VERSION 5.8 ;
BUSBITCHARS "[]" ;
DIVIDERCHAR "/" ;
UNITS
    DATABASE MICRONS 1000 ;
END UNITS

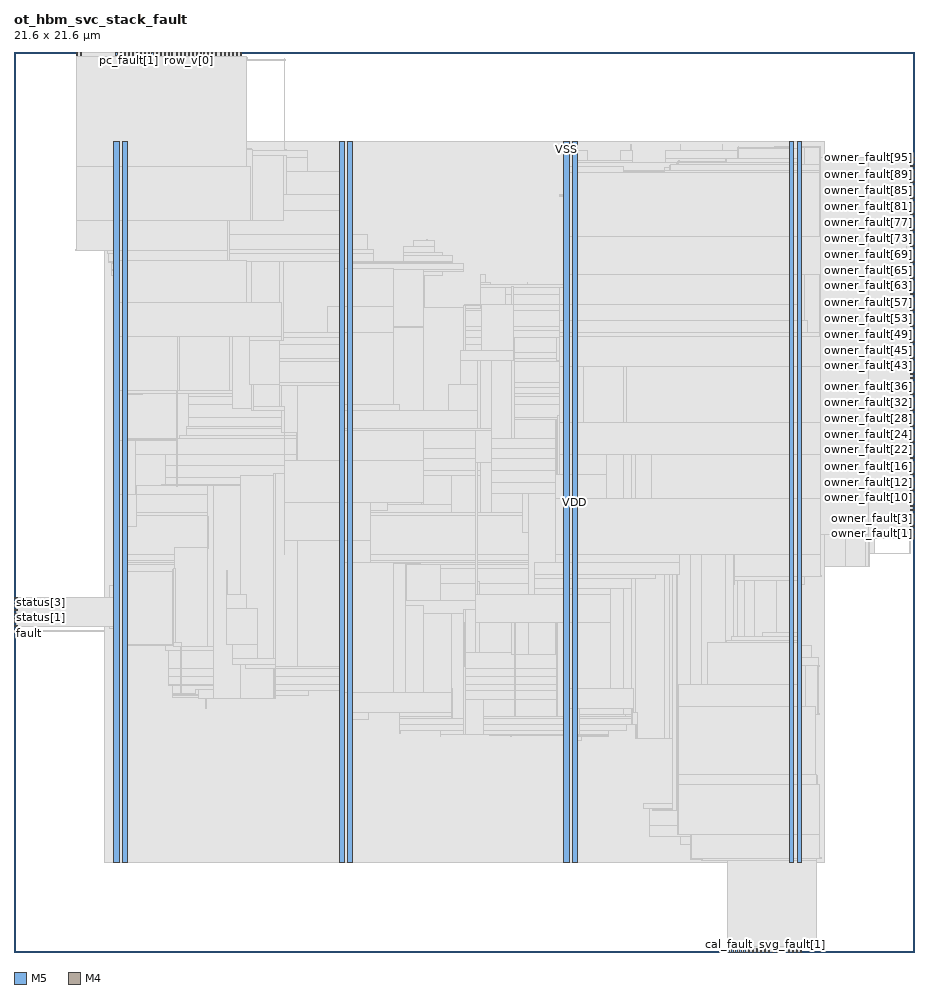
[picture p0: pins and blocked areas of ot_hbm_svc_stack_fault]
MACRO ot_hbm_svc_stack_fault
  FOREIGN ot_hbm_svc_stack_fault 0 0 ;
  CLASS BLOCK ;
  SIZE 21.6 BY 21.6 ;
  PIN cal_fault
    DIRECTION INPUT ;
    USE SIGNAL ;
    PORT
      LAYER M5 ;
        RECT  17.136 0 17.16 0.084 ;
    END
  END cal_fault
  PIN del_fault[0]
    DIRECTION INPUT ;
    USE SIGNAL ;
    PORT
      LAYER M5 ;
        RECT  17.232 0 17.256 0.084 ;
    END
  END del_fault[0]
  PIN del_fault[1]
    DIRECTION INPUT ;
    USE SIGNAL ;
    PORT
      LAYER M5 ;
        RECT  17.328 0 17.352 0.084 ;
    END
  END del_fault[1]
  PIN del_fault[2]
    DIRECTION INPUT ;
    USE SIGNAL ;
    PORT
      LAYER M5 ;
        RECT  17.424 0 17.448 0.084 ;
    END
  END del_fault[2]
  PIN del_fault[3]
    DIRECTION INPUT ;
    USE SIGNAL ;
    PORT
      LAYER M5 ;
        RECT  17.52 0 17.544 0.084 ;
    END
  END del_fault[3]
  PIN del_fault[4]
    DIRECTION INPUT ;
    USE SIGNAL ;
    PORT
      LAYER M5 ;
        RECT  17.616 0 17.64 0.084 ;
    END
  END del_fault[4]
  PIN del_fault[5]
    DIRECTION INPUT ;
    USE SIGNAL ;
    PORT
      LAYER M5 ;
        RECT  17.712 0 17.736 0.084 ;
    END
  END del_fault[5]
  PIN del_fault[6]
    DIRECTION INPUT ;
    USE SIGNAL ;
    PORT
      LAYER M5 ;
        RECT  17.808 0 17.832 0.084 ;
    END
  END del_fault[6]
  PIN del_fault[7]
    DIRECTION INPUT ;
    USE SIGNAL ;
    PORT
      LAYER M5 ;
        RECT  17.904 0 17.928 0.084 ;
    END
  END del_fault[7]
  PIN fault
    DIRECTION OUTPUT ;
    USE SIGNAL ;
    PORT
      LAYER M4 ;
        RECT  0 7.824 0.084 7.848 ;
    END
  END fault
  PIN hbm_clk
    DIRECTION INPUT ;
    USE SIGNAL ;
    PORT
      LAYER M5 ;
        RECT  2.448 21.516 2.472 21.6 ;
    END
  END hbm_clk
  PIN hbm_rst_n
    DIRECTION INPUT ;
    USE SIGNAL ;
    PORT
      LAYER M5 ;
        RECT  2.544 21.516 2.568 21.6 ;
    END
  END hbm_rst_n
  PIN owner_fault[0]
    DIRECTION INPUT ;
    USE SIGNAL ;
    PORT
      LAYER M4 ;
        RECT  21.516 9.936 21.6 9.96 ;
    END
  END owner_fault[0]
  PIN owner_fault[10]
    DIRECTION INPUT ;
    USE SIGNAL ;
    PORT
      LAYER M4 ;
        RECT  21.516 10.896 21.6 10.92 ;
    END
  END owner_fault[10]
  PIN owner_fault[11]
    DIRECTION INPUT ;
    USE SIGNAL ;
    PORT
      LAYER M4 ;
        RECT  21.516 10.992 21.6 11.016 ;
    END
  END owner_fault[11]
  PIN owner_fault[12]
    DIRECTION INPUT ;
    USE SIGNAL ;
    PORT
      LAYER M4 ;
        RECT  21.516 11.088 21.6 11.112 ;
    END
  END owner_fault[12]
  PIN owner_fault[13]
    DIRECTION INPUT ;
    USE SIGNAL ;
    PORT
      LAYER M4 ;
        RECT  21.516 11.184 21.6 11.208 ;
    END
  END owner_fault[13]
  PIN owner_fault[14]
    DIRECTION INPUT ;
    USE SIGNAL ;
    PORT
      LAYER M4 ;
        RECT  21.516 11.28 21.6 11.304 ;
    END
  END owner_fault[14]
  PIN owner_fault[15]
    DIRECTION INPUT ;
    USE SIGNAL ;
    PORT
      LAYER M4 ;
        RECT  21.516 11.376 21.6 11.4 ;
    END
  END owner_fault[15]
  PIN owner_fault[16]
    DIRECTION INPUT ;
    USE SIGNAL ;
    PORT
      LAYER M4 ;
        RECT  21.516 11.472 21.6 11.496 ;
    END
  END owner_fault[16]
  PIN owner_fault[17]
    DIRECTION INPUT ;
    USE SIGNAL ;
    PORT
      LAYER M4 ;
        RECT  21.516 11.568 21.6 11.592 ;
    END
  END owner_fault[17]
  PIN owner_fault[18]
    DIRECTION INPUT ;
    USE SIGNAL ;
    PORT
      LAYER M4 ;
        RECT  21.516 11.664 21.6 11.688 ;
    END
  END owner_fault[18]
  PIN owner_fault[19]
    DIRECTION INPUT ;
    USE SIGNAL ;
    PORT
      LAYER M4 ;
        RECT  21.516 11.76 21.6 11.784 ;
    END
  END owner_fault[19]
  PIN owner_fault[1]
    DIRECTION INPUT ;
    USE SIGNAL ;
    PORT
      LAYER M4 ;
        RECT  21.516 10.032 21.6 10.056 ;
    END
  END owner_fault[1]
  PIN owner_fault[20]
    DIRECTION INPUT ;
    USE SIGNAL ;
    PORT
      LAYER M4 ;
        RECT  21.516 11.856 21.6 11.88 ;
    END
  END owner_fault[20]
  PIN owner_fault[21]
    DIRECTION INPUT ;
    USE SIGNAL ;
    PORT
      LAYER M4 ;
        RECT  21.516 11.952 21.6 11.976 ;
    END
  END owner_fault[21]
  PIN owner_fault[22]
    DIRECTION INPUT ;
    USE SIGNAL ;
    PORT
      LAYER M4 ;
        RECT  21.516 12.048 21.6 12.072 ;
    END
  END owner_fault[22]
  PIN owner_fault[23]
    DIRECTION INPUT ;
    USE SIGNAL ;
    PORT
      LAYER M4 ;
        RECT  21.516 12.144 21.6 12.168 ;
    END
  END owner_fault[23]
  PIN owner_fault[24]
    DIRECTION INPUT ;
    USE SIGNAL ;
    PORT
      LAYER M4 ;
        RECT  21.516 12.24 21.6 12.264 ;
    END
  END owner_fault[24]
  PIN owner_fault[25]
    DIRECTION INPUT ;
    USE SIGNAL ;
    PORT
      LAYER M4 ;
        RECT  21.516 12.336 21.6 12.36 ;
    END
  END owner_fault[25]
  PIN owner_fault[26]
    DIRECTION INPUT ;
    USE SIGNAL ;
    PORT
      LAYER M4 ;
        RECT  21.516 12.432 21.6 12.456 ;
    END
  END owner_fault[26]
  PIN owner_fault[27]
    DIRECTION INPUT ;
    USE SIGNAL ;
    PORT
      LAYER M4 ;
        RECT  21.516 12.528 21.6 12.552 ;
    END
  END owner_fault[27]
  PIN owner_fault[28]
    DIRECTION INPUT ;
    USE SIGNAL ;
    PORT
      LAYER M4 ;
        RECT  21.516 12.624 21.6 12.648 ;
    END
  END owner_fault[28]
  PIN owner_fault[29]
    DIRECTION INPUT ;
    USE SIGNAL ;
    PORT
      LAYER M4 ;
        RECT  21.516 12.72 21.6 12.744 ;
    END
  END owner_fault[29]
  PIN owner_fault[2]
    DIRECTION INPUT ;
    USE SIGNAL ;
    PORT
      LAYER M4 ;
        RECT  21.516 10.128 21.6 10.152 ;
    END
  END owner_fault[2]
  PIN owner_fault[30]
    DIRECTION INPUT ;
    USE SIGNAL ;
    PORT
      LAYER M4 ;
        RECT  21.516 12.816 21.6 12.84 ;
    END
  END owner_fault[30]
  PIN owner_fault[31]
    DIRECTION INPUT ;
    USE SIGNAL ;
    PORT
      LAYER M4 ;
        RECT  21.516 12.912 21.6 12.936 ;
    END
  END owner_fault[31]
  PIN owner_fault[32]
    DIRECTION INPUT ;
    USE SIGNAL ;
    PORT
      LAYER M4 ;
        RECT  21.516 13.008 21.6 13.032 ;
    END
  END owner_fault[32]
  PIN owner_fault[33]
    DIRECTION INPUT ;
    USE SIGNAL ;
    PORT
      LAYER M4 ;
        RECT  21.516 13.104 21.6 13.128 ;
    END
  END owner_fault[33]
  PIN owner_fault[34]
    DIRECTION INPUT ;
    USE SIGNAL ;
    PORT
      LAYER M4 ;
        RECT  21.516 13.2 21.6 13.224 ;
    END
  END owner_fault[34]
  PIN owner_fault[35]
    DIRECTION INPUT ;
    USE SIGNAL ;
    PORT
      LAYER M4 ;
        RECT  21.516 13.296 21.6 13.32 ;
    END
  END owner_fault[35]
  PIN owner_fault[36]
    DIRECTION INPUT ;
    USE SIGNAL ;
    PORT
      LAYER M4 ;
        RECT  21.516 13.392 21.6 13.416 ;
    END
  END owner_fault[36]
  PIN owner_fault[37]
    DIRECTION INPUT ;
    USE SIGNAL ;
    PORT
      LAYER M4 ;
        RECT  21.516 13.488 21.6 13.512 ;
    END
  END owner_fault[37]
  PIN owner_fault[38]
    DIRECTION INPUT ;
    USE SIGNAL ;
    PORT
      LAYER M4 ;
        RECT  21.516 13.584 21.6 13.608 ;
    END
  END owner_fault[38]
  PIN owner_fault[39]
    DIRECTION INPUT ;
    USE SIGNAL ;
    PORT
      LAYER M4 ;
        RECT  21.516 13.68 21.6 13.704 ;
    END
  END owner_fault[39]
  PIN owner_fault[3]
    DIRECTION INPUT ;
    USE SIGNAL ;
    PORT
      LAYER M4 ;
        RECT  21.516 10.224 21.6 10.248 ;
    END
  END owner_fault[3]
  PIN owner_fault[40]
    DIRECTION INPUT ;
    USE SIGNAL ;
    PORT
      LAYER M4 ;
        RECT  21.516 13.776 21.6 13.8 ;
    END
  END owner_fault[40]
  PIN owner_fault[41]
    DIRECTION INPUT ;
    USE SIGNAL ;
    PORT
      LAYER M4 ;
        RECT  21.516 13.872 21.6 13.896 ;
    END
  END owner_fault[41]
  PIN owner_fault[42]
    DIRECTION INPUT ;
    USE SIGNAL ;
    PORT
      LAYER M4 ;
        RECT  21.516 13.968 21.6 13.992 ;
    END
  END owner_fault[42]
  PIN owner_fault[43]
    DIRECTION INPUT ;
    USE SIGNAL ;
    PORT
      LAYER M4 ;
        RECT  21.516 14.064 21.6 14.088 ;
    END
  END owner_fault[43]
  PIN owner_fault[44]
    DIRECTION INPUT ;
    USE SIGNAL ;
    PORT
      LAYER M4 ;
        RECT  21.516 14.16 21.6 14.184 ;
    END
  END owner_fault[44]
  PIN owner_fault[45]
    DIRECTION INPUT ;
    USE SIGNAL ;
    PORT
      LAYER M4 ;
        RECT  21.516 14.256 21.6 14.28 ;
    END
  END owner_fault[45]
  PIN owner_fault[46]
    DIRECTION INPUT ;
    USE SIGNAL ;
    PORT
      LAYER M4 ;
        RECT  21.516 14.352 21.6 14.376 ;
    END
  END owner_fault[46]
  PIN owner_fault[47]
    DIRECTION INPUT ;
    USE SIGNAL ;
    PORT
      LAYER M4 ;
        RECT  21.516 14.448 21.6 14.472 ;
    END
  END owner_fault[47]
  PIN owner_fault[48]
    DIRECTION INPUT ;
    USE SIGNAL ;
    PORT
      LAYER M4 ;
        RECT  21.516 14.544 21.6 14.568 ;
    END
  END owner_fault[48]
  PIN owner_fault[49]
    DIRECTION INPUT ;
    USE SIGNAL ;
    PORT
      LAYER M4 ;
        RECT  21.516 14.64 21.6 14.664 ;
    END
  END owner_fault[49]
  PIN owner_fault[4]
    DIRECTION INPUT ;
    USE SIGNAL ;
    PORT
      LAYER M4 ;
        RECT  21.516 10.32 21.6 10.344 ;
    END
  END owner_fault[4]
  PIN owner_fault[50]
    DIRECTION INPUT ;
    USE SIGNAL ;
    PORT
      LAYER M4 ;
        RECT  21.516 14.736 21.6 14.76 ;
    END
  END owner_fault[50]
  PIN owner_fault[51]
    DIRECTION INPUT ;
    USE SIGNAL ;
    PORT
      LAYER M4 ;
        RECT  21.516 14.832 21.6 14.856 ;
    END
  END owner_fault[51]
  PIN owner_fault[52]
    DIRECTION INPUT ;
    USE SIGNAL ;
    PORT
      LAYER M4 ;
        RECT  21.516 14.928 21.6 14.952 ;
    END
  END owner_fault[52]
  PIN owner_fault[53]
    DIRECTION INPUT ;
    USE SIGNAL ;
    PORT
      LAYER M4 ;
        RECT  21.516 15.024 21.6 15.048 ;
    END
  END owner_fault[53]
  PIN owner_fault[54]
    DIRECTION INPUT ;
    USE SIGNAL ;
    PORT
      LAYER M4 ;
        RECT  21.516 15.12 21.6 15.144 ;
    END
  END owner_fault[54]
  PIN owner_fault[55]
    DIRECTION INPUT ;
    USE SIGNAL ;
    PORT
      LAYER M4 ;
        RECT  21.516 15.216 21.6 15.24 ;
    END
  END owner_fault[55]
  PIN owner_fault[56]
    DIRECTION INPUT ;
    USE SIGNAL ;
    PORT
      LAYER M4 ;
        RECT  21.516 15.312 21.6 15.336 ;
    END
  END owner_fault[56]
  PIN owner_fault[57]
    DIRECTION INPUT ;
    USE SIGNAL ;
    PORT
      LAYER M4 ;
        RECT  21.516 15.408 21.6 15.432 ;
    END
  END owner_fault[57]
  PIN owner_fault[58]
    DIRECTION INPUT ;
    USE SIGNAL ;
    PORT
      LAYER M4 ;
        RECT  21.516 15.504 21.6 15.528 ;
    END
  END owner_fault[58]
  PIN owner_fault[59]
    DIRECTION INPUT ;
    USE SIGNAL ;
    PORT
      LAYER M4 ;
        RECT  21.516 15.6 21.6 15.624 ;
    END
  END owner_fault[59]
  PIN owner_fault[5]
    DIRECTION INPUT ;
    USE SIGNAL ;
    PORT
      LAYER M4 ;
        RECT  21.516 10.416 21.6 10.44 ;
    END
  END owner_fault[5]
  PIN owner_fault[60]
    DIRECTION INPUT ;
    USE SIGNAL ;
    PORT
      LAYER M4 ;
        RECT  21.516 15.696 21.6 15.72 ;
    END
  END owner_fault[60]
  PIN owner_fault[61]
    DIRECTION INPUT ;
    USE SIGNAL ;
    PORT
      LAYER M4 ;
        RECT  21.516 15.792 21.6 15.816 ;
    END
  END owner_fault[61]
  PIN owner_fault[62]
    DIRECTION INPUT ;
    USE SIGNAL ;
    PORT
      LAYER M4 ;
        RECT  21.516 15.888 21.6 15.912 ;
    END
  END owner_fault[62]
  PIN owner_fault[63]
    DIRECTION INPUT ;
    USE SIGNAL ;
    PORT
      LAYER M4 ;
        RECT  21.516 15.984 21.6 16.008 ;
    END
  END owner_fault[63]
  PIN owner_fault[64]
    DIRECTION INPUT ;
    USE SIGNAL ;
    PORT
      LAYER M4 ;
        RECT  21.516 16.08 21.6 16.104 ;
    END
  END owner_fault[64]
  PIN owner_fault[65]
    DIRECTION INPUT ;
    USE SIGNAL ;
    PORT
      LAYER M4 ;
        RECT  21.516 16.176 21.6 16.2 ;
    END
  END owner_fault[65]
  PIN owner_fault[66]
    DIRECTION INPUT ;
    USE SIGNAL ;
    PORT
      LAYER M4 ;
        RECT  21.516 16.272 21.6 16.296 ;
    END
  END owner_fault[66]
  PIN owner_fault[67]
    DIRECTION INPUT ;
    USE SIGNAL ;
    PORT
      LAYER M4 ;
        RECT  21.516 16.368 21.6 16.392 ;
    END
  END owner_fault[67]
  PIN owner_fault[68]
    DIRECTION INPUT ;
    USE SIGNAL ;
    PORT
      LAYER M4 ;
        RECT  21.516 16.464 21.6 16.488 ;
    END
  END owner_fault[68]
  PIN owner_fault[69]
    DIRECTION INPUT ;
    USE SIGNAL ;
    PORT
      LAYER M4 ;
        RECT  21.516 16.56 21.6 16.584 ;
    END
  END owner_fault[69]
  PIN owner_fault[6]
    DIRECTION INPUT ;
    USE SIGNAL ;
    PORT
      LAYER M4 ;
        RECT  21.516 10.512 21.6 10.536 ;
    END
  END owner_fault[6]
  PIN owner_fault[70]
    DIRECTION INPUT ;
    USE SIGNAL ;
    PORT
      LAYER M4 ;
        RECT  21.516 16.656 21.6 16.68 ;
    END
  END owner_fault[70]
  PIN owner_fault[71]
    DIRECTION INPUT ;
    USE SIGNAL ;
    PORT
      LAYER M4 ;
        RECT  21.516 16.752 21.6 16.776 ;
    END
  END owner_fault[71]
  PIN owner_fault[72]
    DIRECTION INPUT ;
    USE SIGNAL ;
    PORT
      LAYER M4 ;
        RECT  21.516 16.848 21.6 16.872 ;
    END
  END owner_fault[72]
  PIN owner_fault[73]
    DIRECTION INPUT ;
    USE SIGNAL ;
    PORT
      LAYER M4 ;
        RECT  21.516 16.944 21.6 16.968 ;
    END
  END owner_fault[73]
  PIN owner_fault[74]
    DIRECTION INPUT ;
    USE SIGNAL ;
    PORT
      LAYER M4 ;
        RECT  21.516 17.04 21.6 17.064 ;
    END
  END owner_fault[74]
  PIN owner_fault[75]
    DIRECTION INPUT ;
    USE SIGNAL ;
    PORT
      LAYER M4 ;
        RECT  21.516 17.136 21.6 17.16 ;
    END
  END owner_fault[75]
  PIN owner_fault[76]
    DIRECTION INPUT ;
    USE SIGNAL ;
    PORT
      LAYER M4 ;
        RECT  21.516 17.232 21.6 17.256 ;
    END
  END owner_fault[76]
  PIN owner_fault[77]
    DIRECTION INPUT ;
    USE SIGNAL ;
    PORT
      LAYER M4 ;
        RECT  21.516 17.328 21.6 17.352 ;
    END
  END owner_fault[77]
  PIN owner_fault[78]
    DIRECTION INPUT ;
    USE SIGNAL ;
    PORT
      LAYER M4 ;
        RECT  21.516 17.424 21.6 17.448 ;
    END
  END owner_fault[78]
  PIN owner_fault[79]
    DIRECTION INPUT ;
    USE SIGNAL ;
    PORT
      LAYER M4 ;
        RECT  21.516 17.52 21.6 17.544 ;
    END
  END owner_fault[79]
  PIN owner_fault[7]
    DIRECTION INPUT ;
    USE SIGNAL ;
    PORT
      LAYER M4 ;
        RECT  21.516 10.608 21.6 10.632 ;
    END
  END owner_fault[7]
  PIN owner_fault[80]
    DIRECTION INPUT ;
    USE SIGNAL ;
    PORT
      LAYER M4 ;
        RECT  21.516 17.616 21.6 17.64 ;
    END
  END owner_fault[80]
  PIN owner_fault[81]
    DIRECTION INPUT ;
    USE SIGNAL ;
    PORT
      LAYER M4 ;
        RECT  21.516 17.712 21.6 17.736 ;
    END
  END owner_fault[81]
  PIN owner_fault[82]
    DIRECTION INPUT ;
    USE SIGNAL ;
    PORT
      LAYER M4 ;
        RECT  21.516 17.808 21.6 17.832 ;
    END
  END owner_fault[82]
  PIN owner_fault[83]
    DIRECTION INPUT ;
    USE SIGNAL ;
    PORT
      LAYER M4 ;
        RECT  21.516 17.904 21.6 17.928 ;
    END
  END owner_fault[83]
  PIN owner_fault[84]
    DIRECTION INPUT ;
    USE SIGNAL ;
    PORT
      LAYER M4 ;
        RECT  21.516 18 21.6 18.024 ;
    END
  END owner_fault[84]
  PIN owner_fault[85]
    DIRECTION INPUT ;
    USE SIGNAL ;
    PORT
      LAYER M4 ;
        RECT  21.516 18.096 21.6 18.12 ;
    END
  END owner_fault[85]
  PIN owner_fault[86]
    DIRECTION INPUT ;
    USE SIGNAL ;
    PORT
      LAYER M4 ;
        RECT  21.516 18.192 21.6 18.216 ;
    END
  END owner_fault[86]
  PIN owner_fault[87]
    DIRECTION INPUT ;
    USE SIGNAL ;
    PORT
      LAYER M4 ;
        RECT  21.516 18.288 21.6 18.312 ;
    END
  END owner_fault[87]
  PIN owner_fault[88]
    DIRECTION INPUT ;
    USE SIGNAL ;
    PORT
      LAYER M4 ;
        RECT  21.516 18.384 21.6 18.408 ;
    END
  END owner_fault[88]
  PIN owner_fault[89]
    DIRECTION INPUT ;
    USE SIGNAL ;
    PORT
      LAYER M4 ;
        RECT  21.516 18.48 21.6 18.504 ;
    END
  END owner_fault[89]
  PIN owner_fault[8]
    DIRECTION INPUT ;
    USE SIGNAL ;
    PORT
      LAYER M4 ;
        RECT  21.516 10.704 21.6 10.728 ;
    END
  END owner_fault[8]
  PIN owner_fault[90]
    DIRECTION INPUT ;
    USE SIGNAL ;
    PORT
      LAYER M4 ;
        RECT  21.516 18.576 21.6 18.6 ;
    END
  END owner_fault[90]
  PIN owner_fault[91]
    DIRECTION INPUT ;
    USE SIGNAL ;
    PORT
      LAYER M4 ;
        RECT  21.516 18.672 21.6 18.696 ;
    END
  END owner_fault[91]
  PIN owner_fault[92]
    DIRECTION INPUT ;
    USE SIGNAL ;
    PORT
      LAYER M4 ;
        RECT  21.516 18.768 21.6 18.792 ;
    END
  END owner_fault[92]
  PIN owner_fault[93]
    DIRECTION INPUT ;
    USE SIGNAL ;
    PORT
      LAYER M4 ;
        RECT  21.516 18.864 21.6 18.888 ;
    END
  END owner_fault[93]
  PIN owner_fault[94]
    DIRECTION INPUT ;
    USE SIGNAL ;
    PORT
      LAYER M4 ;
        RECT  21.516 18.96 21.6 18.984 ;
    END
  END owner_fault[94]
  PIN owner_fault[95]
    DIRECTION INPUT ;
    USE SIGNAL ;
    PORT
      LAYER M4 ;
        RECT  21.516 19.056 21.6 19.08 ;
    END
  END owner_fault[95]
  PIN owner_fault[9]
    DIRECTION INPUT ;
    USE SIGNAL ;
    PORT
      LAYER M4 ;
        RECT  21.516 10.8 21.6 10.824 ;
    END
  END owner_fault[9]
  PIN pc_fault[0]
    DIRECTION INPUT ;
    USE SIGNAL ;
    PORT
      LAYER M5 ;
        RECT  2.64 21.516 2.664 21.6 ;
    END
  END pc_fault[0]
  PIN pc_fault[10]
    DIRECTION INPUT ;
    USE SIGNAL ;
    PORT
      LAYER M5 ;
        RECT  3.6 21.516 3.624 21.6 ;
    END
  END pc_fault[10]
  PIN pc_fault[11]
    DIRECTION INPUT ;
    USE SIGNAL ;
    PORT
      LAYER M5 ;
        RECT  3.696 21.516 3.72 21.6 ;
    END
  END pc_fault[11]
  PIN pc_fault[12]
    DIRECTION INPUT ;
    USE SIGNAL ;
    PORT
      LAYER M5 ;
        RECT  3.792 21.516 3.816 21.6 ;
    END
  END pc_fault[12]
  PIN pc_fault[13]
    DIRECTION INPUT ;
    USE SIGNAL ;
    PORT
      LAYER M5 ;
        RECT  3.888 21.516 3.912 21.6 ;
    END
  END pc_fault[13]
  PIN pc_fault[14]
    DIRECTION INPUT ;
    USE SIGNAL ;
    PORT
      LAYER M5 ;
        RECT  3.984 21.516 4.008 21.6 ;
    END
  END pc_fault[14]
  PIN pc_fault[15]
    DIRECTION INPUT ;
    USE SIGNAL ;
    PORT
      LAYER M5 ;
        RECT  4.08 21.516 4.104 21.6 ;
    END
  END pc_fault[15]
  PIN pc_fault[1]
    DIRECTION INPUT ;
    USE SIGNAL ;
    PORT
      LAYER M5 ;
        RECT  2.736 21.516 2.76 21.6 ;
    END
  END pc_fault[1]
  PIN pc_fault[2]
    DIRECTION INPUT ;
    USE SIGNAL ;
    PORT
      LAYER M5 ;
        RECT  2.832 21.516 2.856 21.6 ;
    END
  END pc_fault[2]
  PIN pc_fault[3]
    DIRECTION INPUT ;
    USE SIGNAL ;
    PORT
      LAYER M5 ;
        RECT  2.928 21.516 2.952 21.6 ;
    END
  END pc_fault[3]
  PIN pc_fault[4]
    DIRECTION INPUT ;
    USE SIGNAL ;
    PORT
      LAYER M5 ;
        RECT  3.024 21.516 3.048 21.6 ;
    END
  END pc_fault[4]
  PIN pc_fault[5]
    DIRECTION INPUT ;
    USE SIGNAL ;
    PORT
      LAYER M5 ;
        RECT  3.12 21.516 3.144 21.6 ;
    END
  END pc_fault[5]
  PIN pc_fault[6]
    DIRECTION INPUT ;
    USE SIGNAL ;
    PORT
      LAYER M5 ;
        RECT  3.216 21.516 3.24 21.6 ;
    END
  END pc_fault[6]
  PIN pc_fault[7]
    DIRECTION INPUT ;
    USE SIGNAL ;
    PORT
      LAYER M5 ;
        RECT  3.312 21.516 3.336 21.6 ;
    END
  END pc_fault[7]
  PIN pc_fault[8]
    DIRECTION INPUT ;
    USE SIGNAL ;
    PORT
      LAYER M5 ;
        RECT  3.408 21.516 3.432 21.6 ;
    END
  END pc_fault[8]
  PIN pc_fault[9]
    DIRECTION INPUT ;
    USE SIGNAL ;
    PORT
      LAYER M5 ;
        RECT  3.504 21.516 3.528 21.6 ;
    END
  END pc_fault[9]
  PIN row_v[0]
    DIRECTION INPUT ;
    USE SIGNAL ;
    PORT
      LAYER M5 ;
        RECT  4.176 21.516 4.2 21.6 ;
    END
  END row_v[0]
  PIN row_v[10]
    DIRECTION INPUT ;
    USE SIGNAL ;
    PORT
      LAYER M5 ;
        RECT  5.136 21.516 5.16 21.6 ;
    END
  END row_v[10]
  PIN row_v[11]
    DIRECTION INPUT ;
    USE SIGNAL ;
    PORT
      LAYER M5 ;
        RECT  5.232 21.516 5.256 21.6 ;
    END
  END row_v[11]
  PIN row_v[12]
    DIRECTION INPUT ;
    USE SIGNAL ;
    PORT
      LAYER M5 ;
        RECT  5.328 21.516 5.352 21.6 ;
    END
  END row_v[12]
  PIN row_v[13]
    DIRECTION INPUT ;
    USE SIGNAL ;
    PORT
      LAYER M5 ;
        RECT  5.424 21.516 5.448 21.6 ;
    END
  END row_v[13]
  PIN row_v[14]
    DIRECTION INPUT ;
    USE SIGNAL ;
    PORT
      LAYER M5 ;
        RECT  1.488 21.516 1.512 21.6 ;
    END
  END row_v[14]
  PIN row_v[15]
    DIRECTION INPUT ;
    USE SIGNAL ;
    PORT
      LAYER M5 ;
        RECT  1.584 21.516 1.608 21.6 ;
    END
  END row_v[15]
  PIN row_v[1]
    DIRECTION INPUT ;
    USE SIGNAL ;
    PORT
      LAYER M5 ;
        RECT  4.272 21.516 4.296 21.6 ;
    END
  END row_v[1]
  PIN row_v[2]
    DIRECTION INPUT ;
    USE SIGNAL ;
    PORT
      LAYER M5 ;
        RECT  4.368 21.516 4.392 21.6 ;
    END
  END row_v[2]
  PIN row_v[3]
    DIRECTION INPUT ;
    USE SIGNAL ;
    PORT
      LAYER M5 ;
        RECT  4.464 21.516 4.488 21.6 ;
    END
  END row_v[3]
  PIN row_v[4]
    DIRECTION INPUT ;
    USE SIGNAL ;
    PORT
      LAYER M5 ;
        RECT  4.56 21.516 4.584 21.6 ;
    END
  END row_v[4]
  PIN row_v[5]
    DIRECTION INPUT ;
    USE SIGNAL ;
    PORT
      LAYER M5 ;
        RECT  4.656 21.516 4.68 21.6 ;
    END
  END row_v[5]
  PIN row_v[6]
    DIRECTION INPUT ;
    USE SIGNAL ;
    PORT
      LAYER M5 ;
        RECT  4.752 21.516 4.776 21.6 ;
    END
  END row_v[6]
  PIN row_v[7]
    DIRECTION INPUT ;
    USE SIGNAL ;
    PORT
      LAYER M5 ;
        RECT  4.848 21.516 4.872 21.6 ;
    END
  END row_v[7]
  PIN row_v[8]
    DIRECTION INPUT ;
    USE SIGNAL ;
    PORT
      LAYER M5 ;
        RECT  4.944 21.516 4.968 21.6 ;
    END
  END row_v[8]
  PIN row_v[9]
    DIRECTION INPUT ;
    USE SIGNAL ;
    PORT
      LAYER M5 ;
        RECT  5.04 21.516 5.064 21.6 ;
    END
  END row_v[9]
  PIN share_fault[0]
    DIRECTION INPUT ;
    USE SIGNAL ;
    PORT
      LAYER M5 ;
        RECT  18 0 18.024 0.084 ;
    END
  END share_fault[0]
  PIN share_fault[1]
    DIRECTION INPUT ;
    USE SIGNAL ;
    PORT
      LAYER M5 ;
        RECT  18.096 0 18.12 0.084 ;
    END
  END share_fault[1]
  PIN share_fault[2]
    DIRECTION INPUT ;
    USE SIGNAL ;
    PORT
      LAYER M5 ;
        RECT  18.192 0 18.216 0.084 ;
    END
  END share_fault[2]
  PIN share_fault[3]
    DIRECTION INPUT ;
    USE SIGNAL ;
    PORT
      LAYER M5 ;
        RECT  18.288 0 18.312 0.084 ;
    END
  END share_fault[3]
  PIN status[0]
    DIRECTION OUTPUT ;
    USE SIGNAL ;
    PORT
      LAYER M4 ;
        RECT  0 7.92 0.084 7.944 ;
    END
  END status[0]
  PIN status[1]
    DIRECTION OUTPUT ;
    USE SIGNAL ;
    PORT
      LAYER M4 ;
        RECT  0 8.016 0.084 8.04 ;
    END
  END status[1]
  PIN status[2]
    DIRECTION OUTPUT ;
    USE SIGNAL ;
    PORT
      LAYER M4 ;
        RECT  0 8.112 0.084 8.136 ;
    END
  END status[2]
  PIN status[3]
    DIRECTION OUTPUT ;
    USE SIGNAL ;
    PORT
      LAYER M4 ;
        RECT  0 8.208 0.084 8.232 ;
    END
  END status[3]
  PIN status[4]
    DIRECTION OUTPUT ;
    USE SIGNAL ;
    PORT
      LAYER M4 ;
        RECT  0 8.304 0.084 8.328 ;
    END
  END status[4]
  PIN status[5]
    DIRECTION OUTPUT ;
    USE SIGNAL ;
    PORT
      LAYER M4 ;
        RECT  0 8.4 0.084 8.424 ;
    END
  END status[5]
  PIN status[6]
    DIRECTION OUTPUT ;
    USE SIGNAL ;
    PORT
      LAYER M4 ;
        RECT  0 8.496 0.084 8.52 ;
    END
  END status[6]
  PIN stream_clk
    DIRECTION INPUT ;
    USE SIGNAL ;
    PORT
      LAYER M5 ;
        RECT  18.384 0 18.408 0.084 ;
    END
  END stream_clk
  PIN stream_rst_n
    DIRECTION INPUT ;
    USE SIGNAL ;
    PORT
      LAYER M5 ;
        RECT  18.48 0 18.504 0.084 ;
    END
  END stream_rst_n
  PIN svg_fault[0]
    DIRECTION INPUT ;
    USE SIGNAL ;
    PORT
      LAYER M5 ;
        RECT  18.576 0 18.6 0.084 ;
    END
  END svg_fault[0]
  PIN svg_fault[1]
    DIRECTION INPUT ;
    USE SIGNAL ;
    PORT
      LAYER M5 ;
        RECT  18.672 0 18.696 0.084 ;
    END
  END svg_fault[1]
  PIN svg_fault[2]
    DIRECTION INPUT ;
    USE SIGNAL ;
    PORT
      LAYER M5 ;
        RECT  18.768 0 18.792 0.084 ;
    END
  END svg_fault[2]
  PIN svg_fault[3]
    DIRECTION INPUT ;
    USE SIGNAL ;
    PORT
      LAYER M5 ;
        RECT  18.864 0 18.888 0.084 ;
    END
  END svg_fault[3]
  PIN VDD
    DIRECTION INOUT ;
    USE POWER ;
    PORT
      LAYER M5 ;
        RECT  18.792 2.151 18.912 19.449 ;
        RECT  13.392 2.151 13.512 19.449 ;
        RECT  7.992 2.151 8.112 19.449 ;
        RECT  2.592 2.151 2.712 19.449 ;
    END
  END VDD
  PIN VSS
    DIRECTION INOUT ;
    USE GROUND ;
    PORT
      LAYER M5 ;
        RECT  18.6 2.137 18.72 19.463 ;
        RECT  13.2 2.137 13.32 19.463 ;
        RECT  7.8 2.137 7.92 19.463 ;
        RECT  2.4 2.137 2.52 19.463 ;
    END
  END VSS
  OBS
    LAYER RVTN ;
     RECT  2.16 2.16 19.44 2.295 ;
     RECT  2.16 2.565 19.44 2.835 ;
     RECT  2.16 3.105 19.44 3.375 ;
     RECT  2.16 3.645 19.44 3.915 ;
     RECT  2.16 4.185 19.44 4.455 ;
     RECT  2.16 4.725 19.44 4.995 ;
     RECT  2.16 5.265 19.44 5.535 ;
     RECT  2.16 5.805 19.44 6.075 ;
     RECT  2.16 6.345 19.44 6.615 ;
     RECT  2.16 6.885 19.44 7.155 ;
     RECT  2.16 7.425 19.44 7.695 ;
     RECT  2.16 7.965 19.44 8.235 ;
     RECT  2.16 8.505 19.44 8.775 ;
     RECT  2.16 9.045 19.44 9.315 ;
     RECT  2.16 9.585 19.44 9.855 ;
     RECT  2.16 10.125 19.44 10.395 ;
     RECT  2.16 10.665 19.44 10.935 ;
     RECT  2.16 11.205 19.44 11.475 ;
     RECT  2.16 11.745 19.44 12.015 ;
     RECT  2.16 12.285 19.44 12.555 ;
     RECT  2.16 12.825 19.44 13.095 ;
     RECT  2.16 13.365 19.44 13.635 ;
     RECT  2.16 13.905 19.44 14.175 ;
     RECT  2.16 14.445 19.44 14.715 ;
     RECT  2.16 14.985 19.44 15.255 ;
     RECT  2.16 15.525 19.44 15.795 ;
     RECT  2.16 16.065 19.44 16.335 ;
     RECT  2.16 16.605 19.44 16.875 ;
     RECT  2.16 17.145 19.44 17.415 ;
     RECT  2.16 17.685 19.44 17.955 ;
     RECT  2.16 18.225 19.44 18.495 ;
     RECT  2.16 18.765 19.44 19.035 ;
     RECT  2.16 19.305 19.44 19.44 ;
    LAYER RVTP ;
     RECT  2.16 2.295 19.44 2.565 ;
     RECT  2.16 2.835 19.44 3.105 ;
     RECT  2.16 3.375 19.44 3.645 ;
     RECT  2.16 3.915 19.44 4.185 ;
     RECT  2.16 4.455 19.44 4.725 ;
     RECT  2.16 4.995 19.44 5.265 ;
     RECT  2.16 5.535 19.44 5.805 ;
     RECT  2.16 6.075 19.44 6.345 ;
     RECT  2.16 6.615 19.44 6.885 ;
     RECT  2.16 7.155 19.44 7.425 ;
     RECT  2.16 7.695 19.44 7.965 ;
     RECT  2.16 8.235 19.44 8.505 ;
     RECT  2.16 8.775 19.44 9.045 ;
     RECT  2.16 9.315 19.44 9.585 ;
     RECT  2.16 9.855 19.44 10.125 ;
     RECT  2.16 10.395 19.44 10.665 ;
     RECT  2.16 10.935 19.44 11.205 ;
     RECT  2.16 11.475 19.44 11.745 ;
     RECT  2.16 12.015 19.44 12.285 ;
     RECT  2.16 12.555 19.44 12.825 ;
     RECT  2.16 13.095 19.44 13.365 ;
     RECT  2.16 13.635 19.44 13.905 ;
     RECT  2.16 14.175 19.44 14.445 ;
     RECT  2.16 14.715 19.44 14.985 ;
     RECT  2.16 15.255 19.44 15.525 ;
     RECT  2.16 15.795 19.44 16.065 ;
     RECT  2.16 16.335 19.44 16.605 ;
     RECT  2.16 16.875 19.44 17.145 ;
     RECT  2.16 17.415 19.44 17.685 ;
     RECT  2.16 17.955 19.44 18.225 ;
     RECT  2.16 18.495 19.44 18.765 ;
     RECT  2.16 19.035 19.44 19.305 ;
    LAYER M1 ;
     RECT  2.16 2.151 19.44 19.449 ;
    LAYER M2 ;
     RECT  0.535 7.704 2.16 7.722 ;
     RECT  2.16 2.151 19.44 19.449 ;
     RECT  19.44 9.252 19.967 13.392 ;
     RECT  19.44 14.346 19.967 18.99 ;
     RECT  19.967 14.346 20.219 16.398 ;
     RECT  20.219 16.38 20.327 16.398 ;
     RECT  19.967 9.252 20.435 13.32 ;
     RECT  19.967 17.352 20.435 18.99 ;
     RECT  20.219 14.346 20.471 15.318 ;
     RECT  20.435 9.252 20.507 12.474 ;
     RECT  20.435 13.302 20.507 13.32 ;
     RECT  20.471 14.652 20.507 15.318 ;
     RECT  20.435 17.352 20.507 17.37 ;
     RECT  20.435 18.198 20.507 18.99 ;
     RECT  20.507 9.252 20.543 10.764 ;
     RECT  20.507 12.456 20.543 12.474 ;
     RECT  20.543 9.558 20.651 10.188 ;
     RECT  20.507 18.27 21.443 18.45 ;
     RECT  20.651 9.558 21.515 9.576 ;
     RECT  21.415 11.556 21.515 11.574 ;
     RECT  20.507 15.3 21.515 15.318 ;
     RECT  21.443 18.432 21.515 18.45 ;
    LAYER M3 ;
     RECT  17.784 1.723 18.09 1.771 ;
     RECT  17.532 1.771 18.09 2.011 ;
     RECT  18.828 1.723 18.846 2.011 ;
     RECT  17.532 2.011 18.846 2.191 ;
     RECT  16.812 2.191 18.846 2.227 ;
     RECT  16.236 2.227 18.846 2.251 ;
     RECT  16.236 2.251 19.314 2.291 ;
     RECT  2.415 2.143 2.505 2.413 ;
     RECT  7.815 2.143 7.905 2.413 ;
     RECT  13.215 2.143 13.305 2.413 ;
     RECT  16.236 2.291 19.242 2.569 ;
     RECT  15.984 2.569 19.242 2.767 ;
     RECT  15.264 2.767 19.242 3.029 ;
     RECT  15.264 3.029 19.17 3.451 ;
     RECT  15.12 3.451 19.17 3.569 ;
     RECT  15.948 3.569 19.17 3.877 ;
     RECT  15.948 3.877 19.206 4.081 ;
     RECT  15.948 4.081 19.242 4.363 ;
     RECT  15.804 4.363 19.242 4.415 ;
     RECT  16.344 4.415 19.242 4.649 ;
     RECT  13.215 2.413 13.497 5.071 ;
     RECT  13.215 5.071 13.626 5.161 ;
     RECT  11.916 5.161 11.934 5.197 ;
     RECT  13.215 5.161 14.274 5.197 ;
     RECT  10.224 5.161 10.242 5.227 ;
     RECT  11.412 5.197 14.274 5.227 ;
     RECT  9.252 5.233 9.27 5.305 ;
     RECT  10.224 5.227 14.274 5.305 ;
     RECT  9.252 5.305 14.706 5.461 ;
     RECT  7.815 2.413 8.097 5.575 ;
     RECT  9.252 5.461 14.85 5.605 ;
     RECT  9.252 5.605 15.138 5.645 ;
     RECT  16.344 4.649 19.134 5.707 ;
     RECT  7.815 5.575 8.514 5.737 ;
     RECT  9.252 5.645 14.67 5.737 ;
     RECT  4.608 5.845 4.626 6.079 ;
     RECT  4.428 6.079 4.626 6.091 ;
     RECT  4.428 6.091 5.274 6.115 ;
     RECT  6.156 6.079 6.174 6.115 ;
     RECT  3.816 6.115 5.274 6.151 ;
     RECT  6.084 6.115 6.174 6.151 ;
     RECT  6.084 6.151 7.074 6.277 ;
     RECT  7.815 5.737 14.67 6.277 ;
     RECT  15.912 5.707 19.314 6.379 ;
     RECT  3.816 6.151 5.31 6.385 ;
     RECT  3.708 6.385 5.31 6.421 ;
     RECT  6.084 6.277 14.67 6.421 ;
     RECT  3.708 6.421 14.67 6.619 ;
     RECT  3.708 6.619 14.85 6.808 ;
     RECT  15.84 6.379 19.314 7.079 ;
     RECT  3.708 6.808 14.994 7.231 ;
     RECT  15.84 7.079 19.134 7.349 ;
     RECT  2.415 2.413 2.697 7.357 ;
     RECT  3.636 7.231 14.994 7.357 ;
     RECT  2.415 7.357 14.994 7.393 ;
     RECT  15.84 7.349 18.897 7.619 ;
     RECT  16.884 7.619 18.897 7.709 ;
     RECT  2.415 7.393 15.066 7.771 ;
     RECT  15.84 7.619 16.002 7.771 ;
     RECT  2.304 7.771 16.002 7.889 ;
     RECT  16.884 7.709 17.046 7.889 ;
     RECT  17.82 7.709 18.897 7.889 ;
     RECT  16.884 7.889 16.902 7.925 ;
     RECT  17.856 7.889 18.897 8.069 ;
     RECT  0.54 7.699 0.558 8.141 ;
     RECT  2.304 7.889 15.57 8.429 ;
     RECT  2.304 8.429 9.414 8.501 ;
     RECT  2.304 8.501 8.097 8.807 ;
     RECT  18.615 8.069 18.897 8.827 ;
     RECT  10.224 8.429 15.57 8.851 ;
     RECT  18.615 8.827 18.954 8.941 ;
     RECT  17.316 8.941 17.334 8.977 ;
     RECT  18.468 8.941 18.954 9.019 ;
     RECT  18.396 9.019 18.954 9.067 ;
     RECT  17.208 8.977 17.334 9.085 ;
     RECT  18.396 9.067 19.314 9.085 ;
     RECT  17.208 9.085 19.314 9.113 ;
     RECT  10.224 8.851 15.786 9.211 ;
     RECT  2.415 8.807 8.097 9.307 ;
     RECT  8.82 8.501 9.414 9.307 ;
     RECT  10.224 9.211 15.966 9.307 ;
     RECT  2.415 9.307 15.966 9.355 ;
     RECT  2.415 9.355 16.254 9.403 ;
     RECT  17.208 9.113 19.17 9.403 ;
     RECT  2.415 9.403 19.17 9.545 ;
     RECT  17.244 9.545 19.17 9.931 ;
     RECT  20.52 9.247 20.538 10.093 ;
     RECT  20.52 10.093 20.574 10.165 ;
     RECT  21.492 9.553 21.51 10.253 ;
     RECT  20.52 10.165 20.646 10.363 ;
     RECT  20.484 10.363 20.646 10.411 ;
     RECT  2.415 9.545 16.29 10.471 ;
     RECT  17.244 9.931 19.242 10.471 ;
     RECT  2.415 10.471 19.242 10.541 ;
     RECT  16.884 10.541 19.242 10.597 ;
     RECT  20.376 10.411 20.646 10.597 ;
     RECT  16.884 10.597 20.646 10.697 ;
     RECT  21.42 10.363 21.438 10.733 ;
     RECT  19.944 10.697 20.646 10.829 ;
     RECT  2.415 10.541 16.146 11.003 ;
     RECT  2.415 11.003 6.93 11.129 ;
     RECT  3.528 11.129 6.93 11.213 ;
     RECT  7.668 11.003 16.146 11.275 ;
     RECT  16.884 10.697 19.134 11.275 ;
     RECT  3.636 11.213 6.93 11.399 ;
     RECT  7.668 11.275 19.134 11.551 ;
     RECT  21.42 11.515 21.438 11.551 ;
     RECT  21.42 11.551 21.51 11.579 ;
     RECT  21.492 11.579 21.51 11.597 ;
     RECT  3.636 11.399 6.858 11.669 ;
     RECT  20.484 10.829 20.646 11.755 ;
     RECT  7.668 11.551 19.242 11.849 ;
     RECT  2.415 11.129 2.697 11.947 ;
     RECT  3.636 11.669 6.786 11.947 ;
     RECT  20.448 11.755 20.646 11.981 ;
     RECT  20.448 11.981 20.538 12.043 ;
     RECT  7.74 11.849 19.242 12.091 ;
     RECT  2.415 11.947 6.786 12.317 ;
     RECT  3.96 12.317 6.786 12.389 ;
     RECT  4.14 12.389 6.786 12.559 ;
     RECT  4.14 12.559 6.822 12.571 ;
     RECT  7.74 12.091 19.422 12.571 ;
     RECT  4.14 12.571 19.422 12.623 ;
     RECT  4.176 12.623 19.422 12.829 ;
     RECT  20.412 12.043 20.538 12.829 ;
     RECT  4.176 12.829 20.538 13.133 ;
     RECT  4.176 13.133 20.502 13.325 ;
     RECT  2.415 12.317 2.697 13.369 ;
     RECT  2.415 13.369 3.078 13.405 ;
     RECT  4.176 13.325 19.962 13.405 ;
     RECT  2.415 13.405 19.962 13.559 ;
     RECT  3.636 13.559 19.962 13.667 ;
     RECT  3.636 13.667 3.654 13.703 ;
     RECT  2.415 13.559 2.898 13.709 ;
     RECT  21.384 13.723 21.402 13.771 ;
     RECT  21.276 13.771 21.402 13.901 ;
     RECT  4.5 13.667 19.962 14.171 ;
     RECT  4.752 14.171 19.962 14.251 ;
     RECT  4.752 14.251 20.502 14.573 ;
     RECT  2.415 13.709 2.697 14.731 ;
     RECT  4.752 14.573 19.314 14.747 ;
     RECT  2.415 14.731 3.222 14.755 ;
     RECT  2.415 14.755 4.014 14.917 ;
     RECT  4.752 14.747 19.242 14.917 ;
     RECT  20.412 14.573 20.502 14.981 ;
     RECT  2.415 14.917 19.242 15.005 ;
     RECT  9 15.005 9.018 15.215 ;
     RECT  20.412 14.981 20.43 15.251 ;
     RECT  9.828 15.005 19.242 15.389 ;
     RECT  21.492 15.295 21.51 15.403 ;
     RECT  10.8 15.389 19.242 15.533 ;
     RECT  21.42 15.403 21.51 15.629 ;
     RECT  21.42 15.629 21.438 15.691 ;
     RECT  21.276 15.691 21.438 15.821 ;
     RECT  11.196 15.533 19.242 15.835 ;
     RECT  20.196 15.499 20.214 15.835 ;
     RECT  21.42 15.821 21.438 15.965 ;
     RECT  11.196 15.835 20.214 16.025 ;
     RECT  11.196 16.025 11.43 16.061 ;
     RECT  12.312 16.025 12.33 16.061 ;
     RECT  13.215 16.025 20.214 16.075 ;
     RECT  2.415 15.005 8.097 16.231 ;
     RECT  9.828 15.389 9.846 16.231 ;
     RECT  11.196 16.061 11.322 16.259 ;
     RECT  9.828 16.231 10.278 16.339 ;
     RECT  2.34 16.231 8.097 16.363 ;
     RECT  2.34 16.363 8.694 16.375 ;
     RECT  9.828 16.339 10.782 16.375 ;
     RECT  13.215 16.075 20.322 16.403 ;
     RECT  2.34 16.375 10.782 16.529 ;
     RECT  2.34 16.529 10.53 16.537 ;
     RECT  2.268 16.537 10.53 16.565 ;
     RECT  21.348 16.603 21.366 16.651 ;
     RECT  9.36 16.565 10.53 16.709 ;
     RECT  2.268 16.565 8.622 16.771 ;
     RECT  21.276 16.651 21.366 16.781 ;
     RECT  9.36 16.709 10.278 16.799 ;
     RECT  2.232 16.771 8.622 16.871 ;
     RECT  9.36 16.799 10.098 16.943 ;
     RECT  13.215 16.403 19.962 16.979 ;
     RECT  9.576 16.943 10.098 17.069 ;
     RECT  21.348 16.781 21.366 17.069 ;
     RECT  9.9 17.069 9.918 17.105 ;
     RECT  2.232 16.871 8.478 17.213 ;
     RECT  13.215 16.979 19.422 17.213 ;
     RECT  20.412 17.227 20.502 17.375 ;
     RECT  20.412 17.375 20.43 17.707 ;
     RECT  13.215 17.213 19.206 17.753 ;
     RECT  2.232 17.213 8.097 17.789 ;
     RECT  13.215 17.753 19.17 17.879 ;
     RECT  21.42 17.131 21.438 17.899 ;
     RECT  20.376 17.707 20.43 17.951 ;
     RECT  21.276 17.899 21.438 18.029 ;
     RECT  21.384 18.029 21.438 18.091 ;
     RECT  13.215 17.879 19.062 18.139 ;
     RECT  21.384 18.091 21.51 18.173 ;
     RECT  13.104 18.139 19.062 18.185 ;
     RECT  21.42 18.173 21.51 18.317 ;
     RECT  21.492 18.317 21.51 18.455 ;
     RECT  2.268 17.789 8.097 18.689 ;
     RECT  13.215 18.185 19.062 18.763 ;
     RECT  20.448 18.184 20.502 18.869 ;
     RECT  13.215 18.763 19.314 18.959 ;
     RECT  13.215 18.959 14.85 18.995 ;
     RECT  20.484 18.869 20.502 18.995 ;
     RECT  15.624 18.959 19.314 19.051 ;
     RECT  2.268 18.689 7.038 19.067 ;
     RECT  7.815 18.689 8.097 19.187 ;
     RECT  2.304 19.067 7.038 19.229 ;
     RECT  13.215 18.995 13.77 19.229 ;
     RECT  14.544 18.995 14.85 19.229 ;
     RECT  15.624 19.051 19.35 19.229 ;
     RECT  6.48 19.229 6.534 19.265 ;
     RECT  18.18 19.229 19.35 19.265 ;
     RECT  2.304 19.229 5.706 19.277 ;
     RECT  18.252 19.265 19.35 19.325 ;
     RECT  2.304 19.277 5.526 19.337 ;
     RECT  18.252 19.325 18.705 19.337 ;
     RECT  2.304 19.337 4.194 19.373 ;
     RECT  4.968 19.337 5.526 19.373 ;
     RECT  14.796 19.229 14.814 19.373 ;
     RECT  15.984 19.229 16.002 19.373 ;
     RECT  16.992 19.229 17.01 19.373 ;
     RECT  2.415 19.373 2.862 19.379 ;
     RECT  2.415 19.379 2.646 19.457 ;
     RECT  7.815 19.187 7.905 19.457 ;
     RECT  13.215 19.229 13.305 19.457 ;
     RECT  18.615 19.337 18.705 19.457 ;
     RECT  2.628 19.457 2.646 19.565 ;
     RECT  3.888 19.373 3.906 19.613 ;
     RECT  3.06 21.115 3.078 21.163 ;
     RECT  4.824 21.259 4.842 21.307 ;
     RECT  2.952 21.163 3.258 21.437 ;
     RECT  6.48 19.265 6.498 21.437 ;
     RECT  3.096 21.437 3.114 21.485 ;
     RECT  4.644 21.307 4.842 21.485 ;
    LAYER M4 ;
     RECT  1.477 16.848 2.293 16.872 ;
     RECT  1.573 19.344 2.293 19.368 ;
     RECT  0.06 7.824 2.408 8.52 ;
     RECT  2.293 16.848 2.408 17.496 ;
     RECT  2.293 18.816 2.408 19.368 ;
     RECT  2.293 21.264 2.437 21.288 ;
     RECT  2.408 2.148 2.512 19.452 ;
     RECT  2.437 21.12 2.533 21.288 ;
     RECT  2.512 2.418 2.588 19.452 ;
     RECT  2.588 2.418 2.675 19.56 ;
     RECT  2.675 2.418 2.704 19.368 ;
     RECT  2.533 21.12 2.897 21.336 ;
     RECT  2.704 12.24 2.915 12.312 ;
     RECT  2.704 10.224 2.945 11.208 ;
     RECT  2.897 21.12 3.058 21.432 ;
     RECT  3.058 21.12 3.157 21.48 ;
     RECT  3.157 21.024 3.169 21.48 ;
     RECT  3.169 21.024 3.299 21.432 ;
     RECT  3.299 21.168 3.347 21.432 ;
     RECT  2.704 13.488 3.685 19.368 ;
     RECT  3.685 13.488 3.781 19.416 ;
     RECT  2.704 7.392 3.797 9.144 ;
     RECT  3.797 7.392 3.829 9.192 ;
     RECT  3.829 7.344 3.841 9.192 ;
     RECT  3.781 13.488 3.877 19.512 ;
     RECT  2.915 12.288 3.923 12.312 ;
     RECT  3.877 13.488 3.961 19.608 ;
     RECT  3.805 6.192 4.345 6.216 ;
     RECT  4.345 6.192 4.417 6.312 ;
     RECT  3.347 21.216 4.549 21.432 ;
     RECT  4.549 21.168 4.633 21.432 ;
     RECT  3.841 7.344 4.645 9.72 ;
     RECT  2.945 10.992 4.645 11.208 ;
     RECT  4.417 6.096 4.777 6.312 ;
     RECT  4.645 7.344 4.777 11.208 ;
     RECT  4.633 21.168 4.787 21.48 ;
     RECT  4.787 21.264 4.876 21.48 ;
     RECT  4.876 21.36 4.883 21.48 ;
     RECT  3.961 13.488 5.164 19.368 ;
     RECT  5.164 13.488 5.245 16.584 ;
     RECT  4.777 6.096 5.425 11.208 ;
     RECT  5.164 17.568 5.465 19.368 ;
     RECT  5.465 17.568 5.537 19.32 ;
     RECT  4.883 21.408 5.603 21.48 ;
     RECT  5.245 13.056 5.708 16.584 ;
     RECT  5.537 17.568 5.717 19.272 ;
     RECT  5.425 6.096 6.217 11.448 ;
     RECT  6.217 6.096 6.275 11.496 ;
     RECT  5.708 13.008 6.371 16.584 ;
     RECT  6.371 13.008 6.428 13.608 ;
     RECT  6.371 14.688 6.473 16.584 ;
     RECT  5.717 17.568 6.473 19.128 ;
     RECT  5.603 21.408 6.509 21.432 ;
     RECT  6.473 18.192 6.545 19.128 ;
     RECT  6.275 6.864 6.805 11.496 ;
     RECT  6.428 12.48 6.805 13.608 ;
     RECT  6.805 6.864 7.808 13.608 ;
     RECT  6.473 14.88 7.808 16.584 ;
     RECT  6.545 18.192 7.808 18.744 ;
     RECT  7.808 2.148 7.912 19.452 ;
     RECT  7.912 2.418 8.104 19.182 ;
     RECT  8.104 10.608 8.957 15 ;
     RECT  8.104 16.368 9.107 16.392 ;
     RECT  8.104 6.24 9.389 9.336 ;
     RECT  9.389 9.312 9.749 9.336 ;
     RECT  8.957 10.752 9.817 15 ;
     RECT  9.389 6.24 9.821 8.328 ;
     RECT  9.817 10.752 9.827 15.48 ;
     RECT  9.821 6.24 10.501 8.136 ;
     RECT  9.827 10.752 10.501 11.448 ;
     RECT  10.501 5.616 10.789 8.136 ;
     RECT  9.827 12.528 10.789 15.48 ;
     RECT  10.789 12.528 10.829 15.528 ;
     RECT  10.789 5.232 10.835 8.232 ;
     RECT  10.835 7.2 11.077 8.232 ;
     RECT  11.077 7.2 11.164 8.904 ;
     RECT  10.501 10.56 11.185 11.448 ;
     RECT  10.829 12.528 11.185 14.424 ;
     RECT  10.829 15.456 11.185 15.528 ;
     RECT  10.835 5.232 11.261 6.072 ;
     RECT  11.185 10.56 11.459 14.424 ;
     RECT  11.185 15.456 11.801 15.96 ;
     RECT  11.164 7.2 11.941 8.568 ;
     RECT  11.459 12.336 11.941 14.424 ;
     RECT  11.941 12.336 12.017 14.76 ;
     RECT  11.459 10.56 12.193 11.016 ;
     RECT  11.941 7.152 12.337 8.568 ;
     RECT  12.193 10.08 12.337 11.016 ;
     RECT  12.337 7.152 12.997 11.016 ;
     RECT  12.017 12.336 12.997 12.792 ;
     RECT  11.261 5.664 13.021 6.072 ;
     RECT  12.997 7.152 13.021 12.792 ;
     RECT  12.017 14.4 13.021 14.76 ;
     RECT  13.021 5.664 13.032 12.792 ;
     RECT  13.021 14.208 13.093 14.76 ;
     RECT  11.801 15.792 13.093 15.96 ;
     RECT  13.032 5.664 13.208 12.888 ;
     RECT  13.093 14.208 13.208 15.96 ;
     RECT  13.093 18.144 13.208 18.168 ;
     RECT  13.208 2.148 13.312 19.452 ;
     RECT  13.312 2.418 13.504 19.182 ;
     RECT  13.504 5.232 13.565 18.84 ;
     RECT  13.565 5.712 14.627 18.84 ;
     RECT  14.627 5.712 14.821 18.744 ;
     RECT  14.821 5.472 14.917 18.744 ;
     RECT  14.917 5.136 15.613 18.744 ;
     RECT  15.613 5.136 15.733 18.84 ;
     RECT  15.325 3.408 15.793 3.432 ;
     RECT  15.733 5.136 15.793 18.888 ;
     RECT  15.793 3.408 15.901 18.888 ;
     RECT  15.901 3.408 15.925 18.936 ;
     RECT  15.925 2.832 16.225 18.984 ;
     RECT  16.225 2.256 16.501 18.984 ;
     RECT  16.501 2.208 17.077 18.984 ;
     RECT  17.077 2.208 17.269 19.032 ;
     RECT  17.269 2.16 17.365 19.032 ;
     RECT  17.365 2.16 17.521 19.32 ;
     RECT  17.521 1.776 17.773 19.32 ;
     RECT  17.773 1.728 18.608 19.32 ;
     RECT  18.608 1.728 18.712 19.452 ;
     RECT  18.661 0.096 18.853 0.12 ;
     RECT  18.712 1.728 18.864 19.32 ;
     RECT  18.864 2.256 18.904 19.32 ;
     RECT  18.904 8.832 18.965 19.32 ;
     RECT  18.904 5.28 19.001 6.888 ;
     RECT  18.853 0.096 19.139 0.168 ;
     RECT  18.904 2.256 19.181 4.248 ;
     RECT  19.181 3.888 19.228 4.248 ;
     RECT  19.181 2.256 19.261 2.856 ;
     RECT  19.139 0.144 19.283 0.168 ;
     RECT  19.228 3.984 19.283 4.248 ;
     RECT  19.001 5.712 19.289 6.888 ;
     RECT  19.289 5.712 19.325 5.736 ;
     RECT  19.289 6.864 19.325 6.888 ;
     RECT  19.283 3.984 19.331 4.008 ;
     RECT  18.965 9.024 19.331 19.32 ;
     RECT  19.331 10.032 19.361 19.32 ;
     RECT  19.261 2.256 19.369 2.28 ;
     RECT  19.331 9.024 19.379 9.048 ;
     RECT  19.361 10.032 20.509 19.08 ;
     RECT  20.509 9.936 21.564 19.08 ;
    LAYER M5 ;
     RECT  17.136 0.016 18.888 0.085 ;
     RECT  17.136 0.085 19.128 0.133 ;
     RECT  2.4 2.137 2.52 2.151 ;
     RECT  7.8 2.137 7.92 2.151 ;
     RECT  13.2 2.137 13.32 2.151 ;
     RECT  17.136 0.133 19.272 2.197 ;
     RECT  16.512 2.197 19.272 2.245 ;
     RECT  16.272 2.245 19.32 2.821 ;
     RECT  15.936 2.821 19.32 4.019 ;
     RECT  15.936 4.019 19.272 4.259 ;
     RECT  14.928 5.125 14.952 5.461 ;
     RECT  14.832 5.461 14.952 5.747 ;
     RECT  13.2 2.151 13.512 5.845 ;
     RECT  14.832 5.747 14.856 5.845 ;
     RECT  15.936 4.259 19.224 5.891 ;
     RECT  7.8 2.151 8.112 6.229 ;
     RECT  10.512 5.605 10.536 6.323 ;
     RECT  13.2 5.845 14.856 6.323 ;
     RECT  15.936 5.891 18.912 6.419 ;
     RECT  6.24 6.085 6.264 6.805 ;
     RECT  5.568 6.805 6.264 6.901 ;
     RECT  5.232 6.901 6.264 7.043 ;
     RECT  3.984 6.181 4.008 7.333 ;
     RECT  5.232 7.043 5.832 7.381 ;
     RECT  3.84 7.333 4.008 7.427 ;
     RECT  16.656 6.419 18.912 7.427 ;
     RECT  17.088 7.427 18.912 7.475 ;
     RECT  17.232 7.475 18.912 7.571 ;
     RECT  17.952 7.571 18.912 7.667 ;
     RECT  10.8 6.853 10.824 7.907 ;
     RECT  12 5.653 12.024 7.909 ;
     RECT  13.2 6.323 14.328 7.909 ;
     RECT  5.088 7.381 5.832 8.243 ;
     RECT  5.088 8.243 5.592 8.579 ;
     RECT  11.088 7.909 14.328 8.579 ;
     RECT  12.48 8.579 14.328 8.725 ;
     RECT  17.28 8.821 17.304 8.917 ;
     RECT  18.288 7.667 18.912 8.917 ;
     RECT  12.48 8.725 14.808 8.965 ;
     RECT  17.28 8.917 18.912 9.013 ;
     RECT  12.48 8.965 15.384 9.061 ;
     RECT  5.088 8.579 5.112 9.155 ;
     RECT  3.84 7.427 3.864 9.203 ;
     RECT  7.8 6.229 9.096 9.347 ;
     RECT  12.48 9.061 15.96 9.347 ;
     RECT  13.008 9.347 15.96 9.541 ;
     RECT  17.28 9.013 19.368 9.541 ;
     RECT  6.48 9.541 6.504 9.877 ;
     RECT  7.8 9.347 8.568 9.877 ;
     RECT  4.656 9.685 4.68 10.451 ;
     RECT  6.48 9.877 8.568 10.789 ;
     RECT  9.792 10.741 9.816 10.789 ;
     RECT  13.008 9.541 19.368 10.883 ;
     RECT  2.4 2.151 2.712 10.981 ;
     RECT  13.008 10.883 14.232 11.459 ;
     RECT  11.088 8.579 11.112 11.749 ;
     RECT  6.48 10.789 9.816 11.795 ;
     RECT  13.104 11.459 14.232 11.941 ;
     RECT  15.312 10.883 19.368 11.941 ;
     RECT  2.4 10.981 2.904 12.275 ;
     RECT  7.8 11.795 9.816 12.517 ;
     RECT  11.088 11.749 11.448 12.517 ;
     RECT  7.8 12.517 11.448 12.563 ;
     RECT  13.104 11.941 19.368 12.707 ;
     RECT  7.8 12.563 11.112 12.995 ;
     RECT  6.48 11.795 6.504 12.997 ;
     RECT  5.76 12.997 6.504 13.091 ;
     RECT  7.8 12.995 9.24 13.139 ;
     RECT  2.4 12.275 2.712 13.477 ;
     RECT  3.888 11.173 3.912 13.477 ;
     RECT  10.416 12.995 11.112 13.619 ;
     RECT  5.76 13.091 6.36 13.621 ;
     RECT  13.104 12.707 13.656 14.053 ;
     RECT  14.688 12.707 19.368 14.053 ;
     RECT  10.704 13.619 11.112 14.197 ;
     RECT  10.704 14.197 11.976 14.435 ;
     RECT  5.664 13.621 6.36 14.677 ;
     RECT  13.104 14.053 19.368 14.771 ;
     RECT  2.4 13.477 3.912 14.773 ;
     RECT  5.664 14.677 6.408 14.773 ;
     RECT  13.104 14.771 19.32 14.867 ;
     RECT  7.8 13.139 9.096 14.869 ;
     RECT  13.104 14.867 19.032 15.155 ;
     RECT  7.536 14.869 9.096 15.491 ;
     RECT  11.232 14.435 11.976 15.539 ;
     RECT  13.104 15.155 18.912 15.539 ;
     RECT  2.4 14.773 6.408 15.587 ;
     RECT  11.952 15.539 11.976 15.971 ;
     RECT  13.2 15.539 18.912 16.261 ;
     RECT  7.8 15.491 9.096 16.403 ;
     RECT  2.4 15.587 5.592 16.595 ;
     RECT  2.4 16.595 5.112 16.837 ;
     RECT  21.408 16.741 21.432 16.931 ;
     RECT  13.2 16.261 19.368 17.171 ;
     RECT  1.488 16.837 5.112 17.557 ;
     RECT  13.2 17.171 19.32 18.707 ;
     RECT  15.6 18.707 19.32 18.755 ;
     RECT  1.488 17.557 5.688 18.851 ;
     RECT  13.2 18.707 14.616 18.851 ;
     RECT  15.744 18.755 19.32 18.899 ;
     RECT  15.936 18.899 18.912 18.947 ;
     RECT  15.936 18.947 15.96 18.995 ;
     RECT  17.088 18.947 18.912 19.043 ;
     RECT  17.376 19.043 18.912 19.283 ;
     RECT  17.376 19.283 17.4 19.331 ;
     RECT  7.8 16.403 8.112 19.449 ;
     RECT  13.2 18.851 13.512 19.449 ;
     RECT  18.6 19.283 18.912 19.449 ;
     RECT  7.8 19.449 7.92 19.463 ;
     RECT  13.2 19.449 13.32 19.463 ;
     RECT  18.6 19.449 18.72 19.463 ;
     RECT  1.488 18.851 5.592 21.491 ;
     RECT  1.488 21.491 5.448 21.584 ;
  END
END ot_hbm_svc_stack_fault
END LIBRARY
